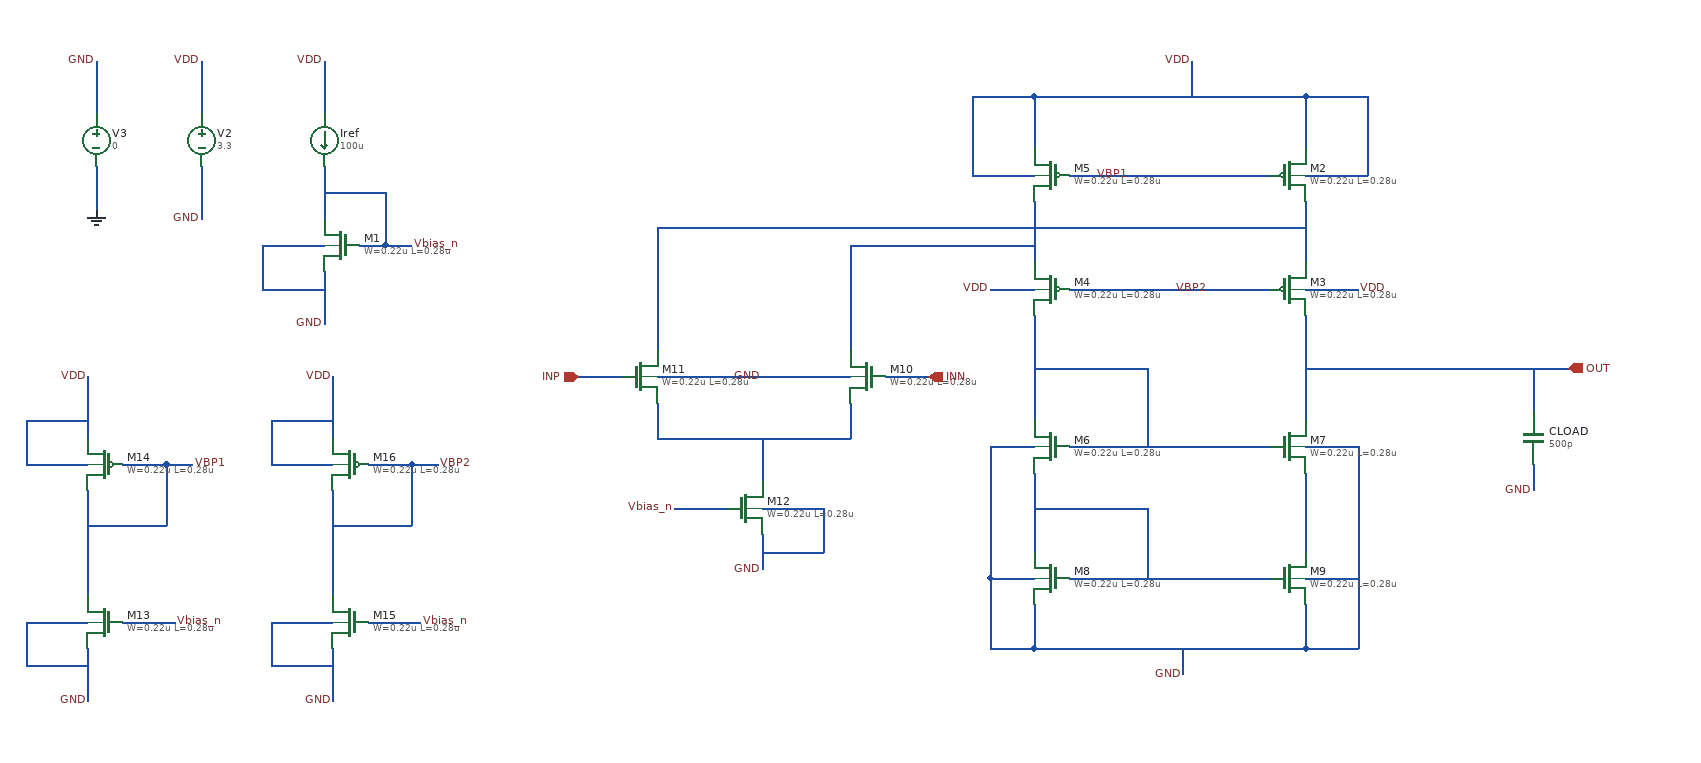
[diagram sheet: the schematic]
v {xschem version=3.4.7 file_version=1.2}
G {}
K {}
V {}
S {}
E {}
P 4 1 -630 -330 {}
N -710 -330 -710 -270 {lab=VDD}
N -570 -330 -570 -270 {lab=VDD}
N -830 -330 -830 -270 {lab=GND}
N -830 -210 -830 -160 {lab=GND}
N -710 -210 -710 -160 {lab=GND}
N -570 -210 -570 -170 {lab=Vbias_n}
N -710 -160 -710 -150 {lab=GND}
N -570 -170 -570 -150 {lab=Vbias_n}
N -570 -180 -500 -180 {lab=Vbias_n}
N -500 -180 -500 -120 {lab=Vbias_n}
N -530 -120 -500 -120 {lab=Vbias_n}
N -500 -120 -470 -120 {lab=Vbias_n}
N -570 -90 -570 -50 {lab=GND}
N -640 -120 -570 -120 {lab=GND}
N -640 -120 -640 -70 {lab=GND}
N -640 -70 -570 -70 {lab=GND}
N -570 -50 -570 -30 {lab=GND}
N 240 -170 240 -100 {lab=#net1}
N 550 -170 550 -100 {lab=#net2}
N 280 -200 510 -200 {lab=VBP1}
N 280 -70 510 -70 {lab=VBP2}
N 240 -40 240 80 {lab=#net3}
N 550 -40 550 80 {lab=OUT}
N 550 20 720 20 {lab=OUT}
N 280 110 510 110 {lab=#net3}
N 240 20 370 20 {lab=#net3}
N 370 20 370 110 {lab=#net3}
N 280 260 510 260 {lab=#net4}
N 550 140 550 200 {lab=#net5}
N 240 180 370 180 {lab=#net4}
N 370 180 370 250 {lab=#net4}
N 370 250 370 260 {lab=#net4}
N 550 200 550 230 {lab=#net5}
N 240 140 240 230 {lab=#net4}
N 240 290 240 340 {lab=GND}
N 240 340 550 340 {lab=GND}
N 550 290 550 340 {lab=GND}
N 410 340 410 370 {lab=GND}
N 240 -290 240 -230 {lab=VDD}
N 240 -290 550 -290 {lab=VDD}
N 550 -290 550 -230 {lab=VDD}
N 420 -330 420 -290 {lab=VDD}
N -190 -140 550 -140 {lab=#net2}
N -190 -140 -190 -30 {lab=#net2}
N -190 -30 -190 -0 {lab=#net2}
N 30 -120 30 -0 {lab=#net1}
N 30 -120 240 -120 {lab=#net1}
N -190 60 -190 100 {lab=#net6}
N -190 100 30 100 {lab=#net6}
N 30 60 30 100 {lab=#net6}
N -70 100 -70 150 {lab=#net6}
N -70 210 -70 250 {lab=GND}
N -170 180 -110 180 {lab=Vbias_n}
N -280 30 -230 30 {lab=INP}
N 70 30 120 30 {lab=INN}
N -840 260 -840 280 {lab=VBP1}
N -800 310 -770 310 {lab=Vbias_n}
N -770 310 -740 310 {lab=Vbias_n}
N -840 340 -840 380 {lab=GND}
N -910 310 -840 310 {lab=GND}
N -910 310 -910 360 {lab=GND}
N -910 360 -840 360 {lab=GND}
N -840 380 -840 400 {lab=GND}
N -840 160 -840 260 {lab=VBP1}
N -70 180 -0 180 {lab=GND}
N -0 180 0 230 {lab=GND}
N -70 230 0 230 {lab=GND}
N -190 30 30 30 {lab=GND}
N 190 260 240 260 {lab=GND}
N 190 260 190 340 {lab=GND}
N 190 340 240 340 {lab=GND}
N 190 110 240 110 {lab=GND}
N 190 110 190 260 {lab=GND}
N 550 110 610 110 {lab=GND}
N 550 340 610 340 {lab=GND}
N 610 110 610 340 {lab=GND}
N 550 260 610 260 {lab=GND}
N 190 -70 240 -70 {lab=VDD}
N 550 -70 610 -70 {lab=VDD}
N 550 -200 620 -200 {lab=VDD}
N 620 -290 620 -200 {lab=VDD}
N 550 -290 620 -290 {lab=VDD}
N 180 -200 240 -200 {lab=VDD}
N 170 -200 180 -200 {lab=VDD}
N 170 -290 170 -200 {lab=VDD}
N 170 -290 240 -290 {lab=VDD}
N -840 30 -840 100 {lab=VDD}
N -840 200 -750 200 {lab=VBP1}
N -750 130 -750 200 {lab=VBP1}
N -800 130 -750 130 {lab=VBP1}
N -750 130 -720 130 {lab=VBP1}
N -560 260 -560 280 {lab=VBP2}
N -520 310 -490 310 {lab=Vbias_n}
N -490 310 -460 310 {lab=Vbias_n}
N -560 340 -560 380 {lab=GND}
N -630 310 -560 310 {lab=GND}
N -630 310 -630 360 {lab=GND}
N -630 360 -560 360 {lab=GND}
N -560 380 -560 400 {lab=GND}
N -560 160 -560 260 {lab=VBP2}
N -560 30 -560 100 {lab=VDD}
N -560 200 -470 200 {lab=VBP2}
N -470 130 -470 200 {lab=VBP2}
N -520 130 -470 130 {lab=VBP2}
N -470 130 -440 130 {lab=VBP2}
N -910 130 -840 130 {lab=VDD}
N -910 80 -910 130 {lab=VDD}
N -910 80 -840 80 {lab=VDD}
N -630 130 -560 130 {lab=VDD}
N -630 80 -630 130 {lab=VDD}
N -630 80 -560 80 {lab=VDD}
N 720 20 850 20 {lab=OUT}
N 810 20 810 70 {lab=OUT}
N 810 130 810 160 {lab=#net7}
C {isource.sym} -570 -240 0 0 {name=Iref value= 100u}
C {lab_pin.sym} -710 -330 0 0 {name=p1 sig_type=std_logic lab=VDD}
C {lab_pin.sym} -570 -330 0 0 {name=p2 sig_type=std_logic lab=VDD}
C {vsource.sym} -710 -240 0 0 {name=V2 value=3.3 savecurrent=false}
C {vsource.sym} -830 -240 0 0 {name=V3 value=0 savecurrent=false}
C {lab_pin.sym} -830 -330 0 0 {name=p3 sig_type=std_logic lab=GND}
C {gnd.sym} -830 -160 0 0 {name=l1 lab=GND}
C {lab_pin.sym} -710 -150 0 0 {name=p4 sig_type=std_logic lab=GND}
C {symbols/nfet_03v3.sym} -550 -120 0 1 {name=M1
L=0.28u
W=0.22u
nf=1
m=1
ad="'int((nf+1)/2) * W/nf * 0.18u'"
pd="'2*int((nf+1)/2) * (W/nf + 0.18u)'"
as="'int((nf+2)/2) * W/nf * 0.18u'"
ps="'2*int((nf+2)/2) * (W/nf + 0.18u)'"
nrd="'0.18u / W'" nrs="'0.18u / W'"
sa=0 sb=0 sd=0
model=nfet_03v3
spiceprefix=X
}
C {lab_pin.sym} -570 -30 0 0 {name=p5 sig_type=std_logic lab=GND}
C {lab_pin.sym} -470 -120 0 1 {name=p6 sig_type=std_logic lab= Vbias_n}
C {symbols/pfet_03v3.sym} 530 -200 0 0 {name=M2
L=0.28u
W=0.22u
nf=1
m=1
ad="'int((nf+1)/2) * W/nf * 0.18u'"
pd="'2*int((nf+1)/2) * (W/nf + 0.18u)'"
as="'int((nf+2)/2) * W/nf * 0.18u'"
ps="'2*int((nf+2)/2) * (W/nf + 0.18u)'"
nrd="'0.18u / W'" nrs="'0.18u / W'"
sa=0 sb=0 sd=0
model=pfet_03v3
spiceprefix=X
}
C {symbols/pfet_03v3.sym} 530 -70 0 0 {name=M3
L=0.28u
W=0.22u
nf=1
m=1
ad="'int((nf+1)/2) * W/nf * 0.18u'"
pd="'2*int((nf+1)/2) * (W/nf + 0.18u)'"
as="'int((nf+2)/2) * W/nf * 0.18u'"
ps="'2*int((nf+2)/2) * (W/nf + 0.18u)'"
nrd="'0.18u / W'" nrs="'0.18u / W'"
sa=0 sb=0 sd=0
model=pfet_03v3
spiceprefix=X
}
C {symbols/pfet_03v3.sym} 260 -70 0 1 {name=M4
L=0.28u
W=0.22u
nf=1
m=1
ad="'int((nf+1)/2) * W/nf * 0.18u'"
pd="'2*int((nf+1)/2) * (W/nf + 0.18u)'"
as="'int((nf+2)/2) * W/nf * 0.18u'"
ps="'2*int((nf+2)/2) * (W/nf + 0.18u)'"
nrd="'0.18u / W'" nrs="'0.18u / W'"
sa=0 sb=0 sd=0
model=pfet_03v3
spiceprefix=X
}
C {symbols/pfet_03v3.sym} 260 -200 0 1 {name=M5
L=0.28u
W=0.22u
nf=1
m=1
ad="'int((nf+1)/2) * W/nf * 0.18u'"
pd="'2*int((nf+1)/2) * (W/nf + 0.18u)'"
as="'int((nf+2)/2) * W/nf * 0.18u'"
ps="'2*int((nf+2)/2) * (W/nf + 0.18u)'"
nrd="'0.18u / W'" nrs="'0.18u / W'"
sa=0 sb=0 sd=0
model=pfet_03v3
spiceprefix=X
}
C {symbols/nfet_03v3.sym} 260 110 0 1 {name=M6
L=0.28u
W=0.22u
nf=1
m=1
ad="'int((nf+1)/2) * W/nf * 0.18u'"
pd="'2*int((nf+1)/2) * (W/nf + 0.18u)'"
as="'int((nf+2)/2) * W/nf * 0.18u'"
ps="'2*int((nf+2)/2) * (W/nf + 0.18u)'"
nrd="'0.18u / W'" nrs="'0.18u / W'"
sa=0 sb=0 sd=0
model=nfet_03v3
spiceprefix=X
}
C {symbols/nfet_03v3.sym} 530 110 0 0 {name=M7
L=0.28u
W=0.22u
nf=1
m=1
ad="'int((nf+1)/2) * W/nf * 0.18u'"
pd="'2*int((nf+1)/2) * (W/nf + 0.18u)'"
as="'int((nf+2)/2) * W/nf * 0.18u'"
ps="'2*int((nf+2)/2) * (W/nf + 0.18u)'"
nrd="'0.18u / W'" nrs="'0.18u / W'"
sa=0 sb=0 sd=0
model=nfet_03v3
spiceprefix=X
}
C {symbols/nfet_03v3.sym} 260 260 0 1 {name=M8
L=0.28u
W=0.22u
nf=1
m=1
ad="'int((nf+1)/2) * W/nf * 0.18u'"
pd="'2*int((nf+1)/2) * (W/nf + 0.18u)'"
as="'int((nf+2)/2) * W/nf * 0.18u'"
ps="'2*int((nf+2)/2) * (W/nf + 0.18u)'"
nrd="'0.18u / W'" nrs="'0.18u / W'"
sa=0 sb=0 sd=0
model=nfet_03v3
spiceprefix=X
}
C {symbols/nfet_03v3.sym} 530 260 0 0 {name=M9
L=0.28u
W=0.22u
nf=1
m=1
ad="'int((nf+1)/2) * W/nf * 0.18u'"
pd="'2*int((nf+1)/2) * (W/nf + 0.18u)'"
as="'int((nf+2)/2) * W/nf * 0.18u'"
ps="'2*int((nf+2)/2) * (W/nf + 0.18u)'"
nrd="'0.18u / W'" nrs="'0.18u / W'"
sa=0 sb=0 sd=0
model=nfet_03v3
spiceprefix=X
}
C {lab_pin.sym} 410 370 0 0 {name=p7 sig_type=std_logic lab=GND}
C {lab_pin.sym} 420 -330 0 0 {name=p8 sig_type=std_logic lab=VDD}
C {opin.sym} 850 20 0 0 {name=p9 lab= OUT}
C {symbols/nfet_03v3.sym} 50 30 0 1 {name=M10
L=0.28u
W=0.22u
nf=1
m=1
ad="'int((nf+1)/2) * W/nf * 0.18u'"
pd="'2*int((nf+1)/2) * (W/nf + 0.18u)'"
as="'int((nf+2)/2) * W/nf * 0.18u'"
ps="'2*int((nf+2)/2) * (W/nf + 0.18u)'"
nrd="'0.18u / W'" nrs="'0.18u / W'"
sa=0 sb=0 sd=0
model=nfet_03v3
spiceprefix=X
}
C {symbols/nfet_03v3.sym} -210 30 0 0 {name=M11
L=0.28u
W=0.22u
nf=1
m=1
ad="'int((nf+1)/2) * W/nf * 0.18u'"
pd="'2*int((nf+1)/2) * (W/nf + 0.18u)'"
as="'int((nf+2)/2) * W/nf * 0.18u'"
ps="'2*int((nf+2)/2) * (W/nf + 0.18u)'"
nrd="'0.18u / W'" nrs="'0.18u / W'"
sa=0 sb=0 sd=0
model=nfet_03v3
spiceprefix=X
}
C {symbols/nfet_03v3.sym} -90 180 0 0 {name=M12
L=0.28u
W=0.22u
nf=1
m=1
ad="'int((nf+1)/2) * W/nf * 0.18u'"
pd="'2*int((nf+1)/2) * (W/nf + 0.18u)'"
as="'int((nf+2)/2) * W/nf * 0.18u'"
ps="'2*int((nf+2)/2) * (W/nf + 0.18u)'"
nrd="'0.18u / W'" nrs="'0.18u / W'"
sa=0 sb=0 sd=0
model=nfet_03v3
spiceprefix=X
}
C {lab_pin.sym} -70 250 0 0 {name=p10 sig_type=std_logic lab=GND}
C {lab_pin.sym} -170 180 0 0 {name=p11 sig_type=std_logic lab= Vbias_n}
C {ipin.sym} -280 30 0 0 {name=p12 lab=INP}
C {ipin.sym} 120 30 0 1 {name=p13 lab=INN}
C {lab_pin.sym} 350 -200 1 0 {name=p14 sig_type=std_logic lab=VBP1}
C {lab_pin.sym} 440 -70 1 0 {name=p15 sig_type=std_logic lab=VBP2}
C {symbols/nfet_03v3.sym} -820 310 0 1 {name=M13
L=0.28u
W=0.22u
nf=1
m=1
ad="'int((nf+1)/2) * W/nf * 0.18u'"
pd="'2*int((nf+1)/2) * (W/nf + 0.18u)'"
as="'int((nf+2)/2) * W/nf * 0.18u'"
ps="'2*int((nf+2)/2) * (W/nf + 0.18u)'"
nrd="'0.18u / W'" nrs="'0.18u / W'"
sa=0 sb=0 sd=0
model=nfet_03v3
spiceprefix=X
}
C {lab_pin.sym} -840 400 0 0 {name=p16 sig_type=std_logic lab=GND}
C {lab_pin.sym} -740 310 0 1 {name=p17 sig_type=std_logic lab= Vbias_n}
C {lab_pin.sym} -70 30 1 0 {name=p18 sig_type=std_logic lab=GND}
C {lab_pin.sym} 190 -70 0 0 {name=p19 sig_type=std_logic lab=VDD}
C {lab_pin.sym} 610 -70 0 1 {name=p20 sig_type=std_logic lab=VDD}
C {symbols/pfet_03v3.sym} -820 130 0 1 {name=M14
L=0.28u
W=0.22u
nf=1
m=1
ad="'int((nf+1)/2) * W/nf * 0.18u'"
pd="'2*int((nf+1)/2) * (W/nf + 0.18u)'"
as="'int((nf+2)/2) * W/nf * 0.18u'"
ps="'2*int((nf+2)/2) * (W/nf + 0.18u)'"
nrd="'0.18u / W'" nrs="'0.18u / W'"
sa=0 sb=0 sd=0
model=pfet_03v3
spiceprefix=X
}
C {lab_pin.sym} -840 30 0 0 {name=p21 sig_type=std_logic lab=VDD}
C {lab_pin.sym} -720 130 0 1 {name=p22 sig_type=std_logic lab= VBP1}
C {symbols/nfet_03v3.sym} -540 310 0 1 {name=M15
L=0.28u
W=0.22u
nf=1
m=1
ad="'int((nf+1)/2) * W/nf * 0.18u'"
pd="'2*int((nf+1)/2) * (W/nf + 0.18u)'"
as="'int((nf+2)/2) * W/nf * 0.18u'"
ps="'2*int((nf+2)/2) * (W/nf + 0.18u)'"
nrd="'0.18u / W'" nrs="'0.18u / W'"
sa=0 sb=0 sd=0
model=nfet_03v3
spiceprefix=X
}
C {lab_pin.sym} -560 400 0 0 {name=p23 sig_type=std_logic lab=GND}
C {lab_pin.sym} -460 310 0 1 {name=p24 sig_type=std_logic lab= Vbias_n}
C {symbols/pfet_03v3.sym} -540 130 0 1 {name=M16
L=0.28u
W=0.22u
nf=1
m=1
ad="'int((nf+1)/2) * W/nf * 0.18u'"
pd="'2*int((nf+1)/2) * (W/nf + 0.18u)'"
as="'int((nf+2)/2) * W/nf * 0.18u'"
ps="'2*int((nf+2)/2) * (W/nf + 0.18u)'"
nrd="'0.18u / W'" nrs="'0.18u / W'"
sa=0 sb=0 sd=0
model=pfet_03v3
spiceprefix=X
}
C {lab_pin.sym} -560 30 0 0 {name=p25 sig_type=std_logic lab=VDD}
C {lab_pin.sym} -440 130 0 1 {name=p26 sig_type=std_logic lab= VBP2}
C {capa.sym} 810 100 0 0 {name=CLOAD
m=1
value=500p
footprint=1206
device="ceramic capacitor"}
C {lab_pin.sym} 810 160 0 0 {name=p27 sig_type=std_logic lab=GND}
